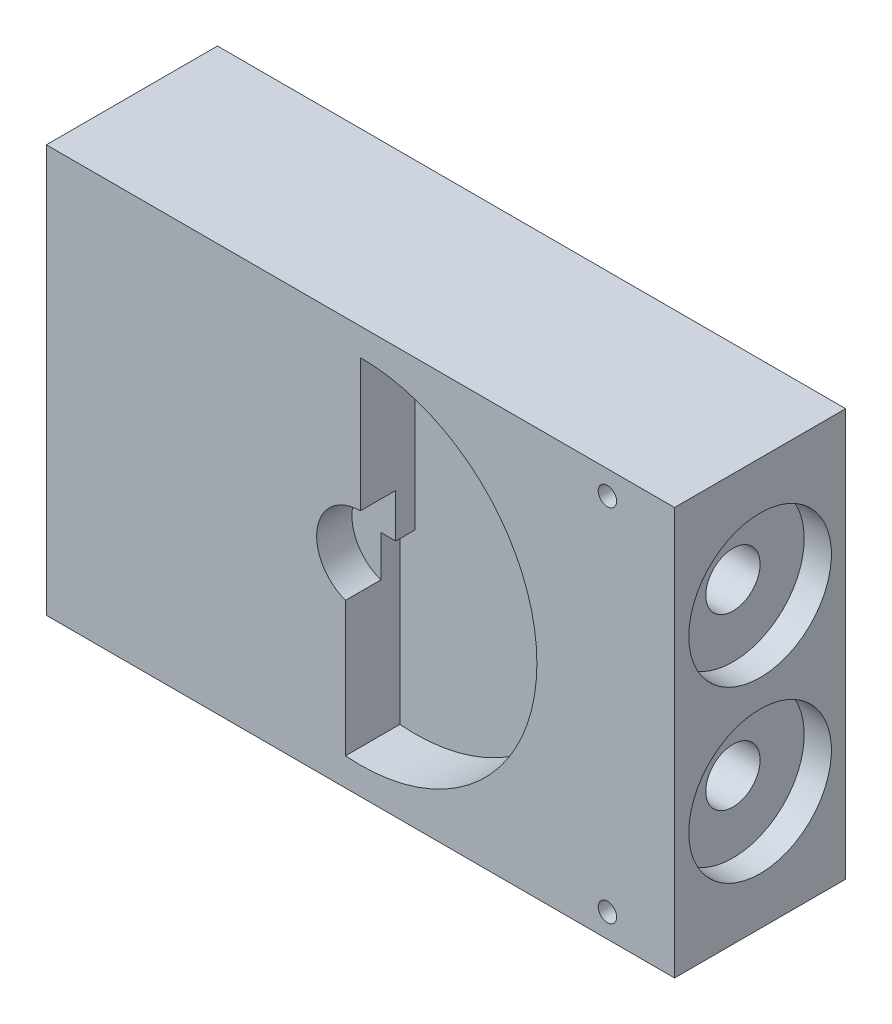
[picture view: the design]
ISO-10303-21;
HEADER;
FILE_DESCRIPTION(('STEP AP214'),'2;1');
FILE_NAME('part.step','',(''),(''),'','','');
FILE_SCHEMA(('AUTOMOTIVE_DESIGN { 1 0 10303 214 1 1 1 1 }'));
ENDSEC;
DATA;
#1=APPLICATION_CONTEXT('core data for automotive mechanical design processes');
#2=APPLICATION_PROTOCOL_DEFINITION('international standard','automotive_design',2000,#1);
#3=PRODUCT_CONTEXT('',#1,'mechanical');
#4=PRODUCT('Part','Part','',(#3));
#5=PRODUCT_RELATED_PRODUCT_CATEGORY('part','',(#4));
#6=PRODUCT_DEFINITION_FORMATION('','',#4);
#7=PRODUCT_DEFINITION_CONTEXT('part definition',#1,'design');
#8=PRODUCT_DEFINITION('design','',#6,#7);
#9=PRODUCT_DEFINITION_SHAPE('','',#8);
#10=(LENGTH_UNIT() NAMED_UNIT(*) SI_UNIT(.MILLI.,.METRE.));
#11=(NAMED_UNIT(*) PLANE_ANGLE_UNIT() SI_UNIT($,.RADIAN.));
#12=(NAMED_UNIT(*) SI_UNIT($,.STERADIAN.) SOLID_ANGLE_UNIT());
#13=UNCERTAINTY_MEASURE_WITH_UNIT(LENGTH_MEASURE(1.E-05),#10,'distance_accuracy_value','');
#14=(GEOMETRIC_REPRESENTATION_CONTEXT(3) GLOBAL_UNCERTAINTY_ASSIGNED_CONTEXT((#13)) GLOBAL_UNIT_ASSIGNED_CONTEXT((#10,
#11,#12)) REPRESENTATION_CONTEXT('',''));
#15=CARTESIAN_POINT('',(0.,0.,0.));
#16=DIRECTION('',(0.,0.,1.));
#17=DIRECTION('',(1.,0.,0.));
#18=AXIS2_PLACEMENT_3D('',#15,#16,#17);
#19=CARTESIAN_POINT('',(29.5275,-16.3368181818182,0.));
#20=DIRECTION('',(1.,0.,0.));
#21=DIRECTION('',(0.,0.,-1.));
#22=AXIS2_PLACEMENT_3D('',#19,#20,#21);
#23=PLANE('',#22);
#24=CARTESIAN_POINT('',(29.5275,-15.875,0.));
#25=DIRECTION('',(-1.,0.,0.));
#26=DIRECTION('',(0.,0.,1.));
#27=AXIS2_PLACEMENT_3D('',#24,#25,#26);
#28=CIRCLE('',#27,5.08);
#29=CARTESIAN_POINT('',(29.5275,-15.875,5.08));
#30=VERTEX_POINT('',#29);
#31=EDGE_CURVE('E224',#30,#30,#28,.F.);
#32=ORIENTED_EDGE('',*,*,#31,.T.);
#33=EDGE_LOOP('',(#32));
#34=FACE_BOUND('',#33,.T.);
#35=ADVANCED_FACE('F38',(#34),#23,.T.);
#36=CARTESIAN_POINT('',(29.5275,15.4131818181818,0.));
#37=DIRECTION('',(1.,0.,0.));
#38=DIRECTION('',(0.,0.,-1.));
#39=AXIS2_PLACEMENT_3D('',#36,#37,#38);
#40=PLANE('',#39);
#41=CARTESIAN_POINT('',(29.5275,15.875,0.));
#42=DIRECTION('',(-1.,0.,0.));
#43=DIRECTION('',(0.,0.,1.));
#44=AXIS2_PLACEMENT_3D('',#41,#42,#43);
#45=CIRCLE('',#44,5.08);
#46=CARTESIAN_POINT('',(29.5275,15.875,5.08000000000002));
#47=VERTEX_POINT('',#46);
#48=EDGE_CURVE('E221',#47,#47,#45,.F.);
#49=ORIENTED_EDGE('',*,*,#48,.T.);
#50=EDGE_LOOP('',(#49));
#51=FACE_BOUND('',#50,.T.);
#52=ADVANCED_FACE('F604',(#51),#40,.T.);
#53=CARTESIAN_POINT('',(53.6575,-15.875,0.));
#54=DIRECTION('',(-1.,0.,0.));
#55=DIRECTION('',(0.,0.,1.));
#56=AXIS2_PLACEMENT_3D('',#53,#54,#55);
#57=CYLINDRICAL_SURFACE('',#56,5.08);
#58=CARTESIAN_POINT('',(53.6575,-15.875,0.));
#59=DIRECTION('',(-1.,0.,0.));
#60=DIRECTION('',(0.,0.,1.));
#61=AXIS2_PLACEMENT_3D('',#58,#59,#60);
#62=CIRCLE('',#61,5.08);
#63=CARTESIAN_POINT('',(53.6575,-15.875,5.08));
#64=VERTEX_POINT('',#63);
#65=EDGE_CURVE('E218',#64,#64,#62,.T.);
#66=ORIENTED_EDGE('',*,*,#65,.F.);
#67=EDGE_LOOP('',(#66));
#68=FACE_BOUND('',#67,.T.);
#69=ORIENTED_EDGE('',*,*,#31,.F.);
#70=EDGE_LOOP('',(#69));
#71=FACE_BOUND('',#70,.T.);
#72=ADVANCED_FACE('F613',(#68,#71),#57,.F.);
#73=CARTESIAN_POINT('',(53.6575,15.875,0.));
#74=DIRECTION('',(-1.,0.,0.));
#75=DIRECTION('',(0.,0.,1.));
#76=AXIS2_PLACEMENT_3D('',#73,#74,#75);
#77=CYLINDRICAL_SURFACE('',#76,5.08);
#78=CARTESIAN_POINT('',(53.6575,15.875,0.));
#79=DIRECTION('',(-1.,0.,0.));
#80=DIRECTION('',(0.,0.,1.));
#81=AXIS2_PLACEMENT_3D('',#78,#79,#80);
#82=CIRCLE('',#81,5.08);
#83=CARTESIAN_POINT('',(53.6575,15.875,5.08000000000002));
#84=VERTEX_POINT('',#83);
#85=EDGE_CURVE('E215',#84,#84,#82,.T.);
#86=ORIENTED_EDGE('',*,*,#85,.F.);
#87=EDGE_LOOP('',(#86));
#88=FACE_BOUND('',#87,.T.);
#89=ORIENTED_EDGE('',*,*,#48,.F.);
#90=EDGE_LOOP('',(#89));
#91=FACE_BOUND('',#90,.T.);
#92=ADVANCED_FACE('F622',(#88,#91),#77,.F.);
#93=CARTESIAN_POINT('',(-32.0397909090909,0.,-6.35));
#94=DIRECTION('',(0.,0.,1.));
#95=DIRECTION('',(1.,0.,0.));
#96=AXIS2_PLACEMENT_3D('',#93,#94,#95);
#97=PLANE('',#96);
#98=CARTESIAN_POINT('',(-31.75,0.,-6.35));
#99=DIRECTION('',(0.,0.,1.));
#100=DIRECTION('',(1.,0.,0.));
#101=AXIS2_PLACEMENT_3D('',#98,#99,#100);
#102=CIRCLE('',#101,3.1877);
#103=CARTESIAN_POINT('',(-28.5623,0.,-6.35));
#104=VERTEX_POINT('',#103);
#105=EDGE_CURVE('E212',#104,#104,#102,.F.);
#106=ORIENTED_EDGE('',*,*,#105,.T.);
#107=EDGE_LOOP('',(#106));
#108=FACE_BOUND('',#107,.T.);
#109=ADVANCED_FACE('F631',(#108),#97,.F.);
#110=CARTESIAN_POINT('',(32.0386363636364,-31.75,-5.08));
#111=DIRECTION('',(0.,0.,1.));
#112=DIRECTION('',(1.,0.,0.));
#113=AXIS2_PLACEMENT_3D('',#110,#111,#112);
#114=PLANE('',#113);
#115=CARTESIAN_POINT('',(31.75,-31.75,-5.08));
#116=DIRECTION('',(0.,0.,1.));
#117=DIRECTION('',(1.,0.,0.));
#118=AXIS2_PLACEMENT_3D('',#115,#116,#117);
#119=CIRCLE('',#118,3.175);
#120=CARTESIAN_POINT('',(34.925,-31.75,-5.08));
#121=VERTEX_POINT('',#120);
#122=EDGE_CURVE('E209',#121,#121,#119,.F.);
#123=ORIENTED_EDGE('',*,*,#122,.T.);
#124=EDGE_LOOP('',(#123));
#125=FACE_BOUND('',#124,.T.);
#126=ADVANCED_FACE('F400',(#125),#114,.F.);
#127=CARTESIAN_POINT('',(28.575,28.5115,-5.08));
#128=DIRECTION('',(0.,0.,1.));
#129=DIRECTION('',(1.,0.,0.));
#130=AXIS2_PLACEMENT_3D('',#127,#128,#129);
#131=PLANE('',#130);
#132=CARTESIAN_POINT('',(31.75,31.75,-5.08));
#133=DIRECTION('',(0.,0.,1.));
#134=DIRECTION('',(1.,0.,0.));
#135=AXIS2_PLACEMENT_3D('',#132,#133,#134);
#136=CIRCLE('',#135,3.175);
#137=CARTESIAN_POINT('',(34.925,31.75,-5.08));
#138=VERTEX_POINT('',#137);
#139=EDGE_CURVE('E206',#138,#138,#136,.F.);
#140=ORIENTED_EDGE('',*,*,#139,.T.);
#141=EDGE_LOOP('',(#140));
#142=FACE_BOUND('',#141,.T.);
#143=ADVANCED_FACE('F396',(#142),#131,.F.);
#144=CARTESIAN_POINT('',(32.0397909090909,0.,-6.35));
#145=DIRECTION('',(0.,0.,1.));
#146=DIRECTION('',(1.,0.,0.));
#147=AXIS2_PLACEMENT_3D('',#144,#145,#146);
#148=PLANE('',#147);
#149=CARTESIAN_POINT('',(31.75,0.,-6.35));
#150=DIRECTION('',(0.,0.,1.));
#151=DIRECTION('',(1.,0.,0.));
#152=AXIS2_PLACEMENT_3D('',#149,#150,#151);
#153=CIRCLE('',#152,3.1877);
#154=CARTESIAN_POINT('',(34.9377,0.,-6.35));
#155=VERTEX_POINT('',#154);
#156=EDGE_CURVE('E203',#155,#155,#153,.F.);
#157=ORIENTED_EDGE('',*,*,#156,.T.);
#158=EDGE_LOOP('',(#157));
#159=FACE_BOUND('',#158,.T.);
#160=ADVANCED_FACE('F399',(#159),#148,.F.);
#161=CARTESIAN_POINT('',(-28.575,-28.5115,-5.08));
#162=DIRECTION('',(0.,0.,1.));
#163=DIRECTION('',(-1.,0.,0.));
#164=AXIS2_PLACEMENT_3D('',#161,#162,#163);
#165=PLANE('',#164);
#166=CARTESIAN_POINT('',(-31.75,-31.75,-5.08));
#167=DIRECTION('',(0.,0.,1.));
#168=DIRECTION('',(1.,0.,0.));
#169=AXIS2_PLACEMENT_3D('',#166,#167,#168);
#170=CIRCLE('',#169,3.175);
#171=CARTESIAN_POINT('',(-28.575,-31.75,-5.08));
#172=VERTEX_POINT('',#171);
#173=EDGE_CURVE('E200',#172,#172,#170,.F.);
#174=ORIENTED_EDGE('',*,*,#173,.T.);
#175=EDGE_LOOP('',(#174));
#176=FACE_BOUND('',#175,.T.);
#177=ADVANCED_FACE('F402',(#176),#165,.F.);
#178=CARTESIAN_POINT('',(-32.0386363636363,31.75,-5.08));
#179=DIRECTION('',(0.,0.,1.));
#180=DIRECTION('',(1.,0.,0.));
#181=AXIS2_PLACEMENT_3D('',#178,#179,#180);
#182=PLANE('',#181);
#183=CARTESIAN_POINT('',(-31.75,31.75,-5.08));
#184=DIRECTION('',(0.,0.,1.));
#185=DIRECTION('',(1.,0.,0.));
#186=AXIS2_PLACEMENT_3D('',#183,#184,#185);
#187=CIRCLE('',#186,3.175);
#188=CARTESIAN_POINT('',(-28.575,31.75,-5.08));
#189=VERTEX_POINT('',#188);
#190=EDGE_CURVE('E197',#189,#189,#187,.F.);
#191=ORIENTED_EDGE('',*,*,#190,.T.);
#192=EDGE_LOOP('',(#191));
#193=FACE_BOUND('',#192,.T.);
#194=ADVANCED_FACE('F405',(#193),#182,.F.);
#195=CARTESIAN_POINT('',(53.6575,-17.0872727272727,0.));
#196=DIRECTION('',(1.,0.,0.));
#197=DIRECTION('',(0.,0.,-1.));
#198=AXIS2_PLACEMENT_3D('',#195,#196,#197);
#199=PLANE('',#198);
#200=ORIENTED_EDGE('',*,*,#65,.T.);
#201=EDGE_LOOP('',(#200));
#202=FACE_BOUND('',#201,.T.);
#203=CARTESIAN_POINT('',(53.6575,-15.875,0.));
#204=DIRECTION('',(-1.,0.,0.));
#205=DIRECTION('',(0.,0.,1.));
#206=AXIS2_PLACEMENT_3D('',#203,#204,#205);
#207=CIRCLE('',#206,13.335);
#208=CARTESIAN_POINT('',(53.6575,-15.875,13.335));
#209=VERTEX_POINT('',#208);
#210=EDGE_CURVE('E194',#209,#209,#207,.F.);
#211=ORIENTED_EDGE('',*,*,#210,.T.);
#212=EDGE_LOOP('',(#211));
#213=FACE_BOUND('',#212,.T.);
#214=ADVANCED_FACE('F664',(#202,#213),#199,.T.);
#215=CARTESIAN_POINT('',(53.6575,14.6627272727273,0.));
#216=DIRECTION('',(1.,0.,0.));
#217=DIRECTION('',(0.,0.,-1.));
#218=AXIS2_PLACEMENT_3D('',#215,#216,#217);
#219=PLANE('',#218);
#220=ORIENTED_EDGE('',*,*,#85,.T.);
#221=EDGE_LOOP('',(#220));
#222=FACE_BOUND('',#221,.T.);
#223=CARTESIAN_POINT('',(53.6575,15.875,0.));
#224=DIRECTION('',(-1.,0.,0.));
#225=DIRECTION('',(0.,0.,1.));
#226=AXIS2_PLACEMENT_3D('',#223,#224,#225);
#227=CIRCLE('',#226,13.335);
#228=CARTESIAN_POINT('',(53.6575,15.875,13.335));
#229=VERTEX_POINT('',#228);
#230=EDGE_CURVE('E191',#229,#229,#227,.F.);
#231=ORIENTED_EDGE('',*,*,#230,.T.);
#232=EDGE_LOOP('',(#231));
#233=FACE_BOUND('',#232,.T.);
#234=ADVANCED_FACE('F673',(#222,#233),#219,.T.);
#235=CARTESIAN_POINT('',(-56.7375,-18.5963723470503,0.));
#236=DIRECTION('',(1.,0.,0.));
#237=DIRECTION('',(0.,0.,-1.));
#238=AXIS2_PLACEMENT_3D('',#235,#236,#237);
#239=PLANE('',#238);
#240=CARTESIAN_POINT('',(-56.7375,-19.05,0.));
#241=DIRECTION('',(1.,0.,0.));
#242=DIRECTION('',(0.,0.,-1.));
#243=AXIS2_PLACEMENT_3D('',#240,#241,#242);
#244=CIRCLE('',#243,4.9899041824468);
#245=CARTESIAN_POINT('',(-56.7375,-19.05,-4.9899041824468));
#246=VERTEX_POINT('',#245);
#247=EDGE_CURVE('E188',#246,#246,#244,.F.);
#248=ORIENTED_EDGE('',*,*,#247,.T.);
#249=EDGE_LOOP('',(#248));
#250=FACE_BOUND('',#249,.T.);
#251=ADVANCED_FACE('F682',(#250),#239,.F.);
#252=CARTESIAN_POINT('',(-55.6895,6.75409090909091,0.));
#253=DIRECTION('',(1.,0.,0.));
#254=DIRECTION('',(0.,0.,-1.));
#255=AXIS2_PLACEMENT_3D('',#252,#253,#254);
#256=PLANE('',#255);
#257=CARTESIAN_POINT('',(-55.6895,7.11200000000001,0.));
#258=DIRECTION('',(-1.,0.,0.));
#259=DIRECTION('',(0.,0.,1.));
#260=AXIS2_PLACEMENT_3D('',#257,#258,#259);
#261=CIRCLE('',#260,3.937);
#262=CARTESIAN_POINT('',(-55.6895,7.11200000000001,3.937));
#263=VERTEX_POINT('',#262);
#264=EDGE_CURVE('E185',#263,#263,#261,.T.);
#265=ORIENTED_EDGE('',*,*,#264,.T.);
#266=EDGE_LOOP('',(#265));
#267=FACE_BOUND('',#266,.T.);
#268=ADVANCED_FACE('F691',(#267),#256,.F.);
#269=CARTESIAN_POINT('',(-55.6895,-7.46990909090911,0.));
#270=DIRECTION('',(1.,0.,0.));
#271=DIRECTION('',(0.,0.,-1.));
#272=AXIS2_PLACEMENT_3D('',#269,#270,#271);
#273=PLANE('',#272);
#274=CARTESIAN_POINT('',(-55.6895,-7.11200000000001,0.));
#275=DIRECTION('',(-1.,0.,0.));
#276=DIRECTION('',(0.,0.,1.));
#277=AXIS2_PLACEMENT_3D('',#274,#275,#276);
#278=CIRCLE('',#277,3.937);
#279=CARTESIAN_POINT('',(-55.6895,-7.11200000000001,3.937));
#280=VERTEX_POINT('',#279);
#281=EDGE_CURVE('E182',#280,#280,#278,.T.);
#282=ORIENTED_EDGE('',*,*,#281,.T.);
#283=EDGE_LOOP('',(#282));
#284=FACE_BOUND('',#283,.T.);
#285=ADVANCED_FACE('F700',(#284),#273,.F.);
#286=CARTESIAN_POINT('',(-56.1975,-32.1367727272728,7.11200000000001));
#287=DIRECTION('',(1.,0.,0.));
#288=DIRECTION('',(0.,0.,-1.));
#289=AXIS2_PLACEMENT_3D('',#286,#287,#288);
#290=PLANE('',#289);
#291=CARTESIAN_POINT('',(-56.1975,-31.75,7.11200000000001));
#292=DIRECTION('',(-1.,0.,0.));
#293=DIRECTION('',(0.,0.,1.));
#294=AXIS2_PLACEMENT_3D('',#291,#292,#293);
#295=CIRCLE('',#294,4.2545);
#296=CARTESIAN_POINT('',(-56.1975,-31.75,11.3665));
#297=VERTEX_POINT('',#296);
#298=EDGE_CURVE('E179',#297,#297,#295,.T.);
#299=ORIENTED_EDGE('',*,*,#298,.T.);
#300=EDGE_LOOP('',(#299));
#301=FACE_BOUND('',#300,.T.);
#302=ADVANCED_FACE('F411',(#301),#290,.F.);
#303=CARTESIAN_POINT('',(-56.1975,4.2545,-11.45159));
#304=DIRECTION('',(1.,0.,0.));
#305=DIRECTION('',(0.,0.,1.));
#306=AXIS2_PLACEMENT_3D('',#303,#304,#305);
#307=PLANE('',#306);
#308=CARTESIAN_POINT('',(-56.1975,0.,-7.112));
#309=DIRECTION('',(-1.,0.,0.));
#310=DIRECTION('',(0.,0.,1.));
#311=AXIS2_PLACEMENT_3D('',#308,#309,#310);
#312=CIRCLE('',#311,4.2545);
#313=CARTESIAN_POINT('',(-56.1975,0.,-2.8575));
#314=VERTEX_POINT('',#313);
#315=EDGE_CURVE('E176',#314,#314,#312,.T.);
#316=ORIENTED_EDGE('',*,*,#315,.T.);
#317=EDGE_LOOP('',(#316));
#318=FACE_BOUND('',#317,.T.);
#319=ADVANCED_FACE('F407',(#318),#307,.F.);
#320=CARTESIAN_POINT('',(-56.1975,27.4955,11.45159));
#321=DIRECTION('',(1.,0.,0.));
#322=DIRECTION('',(0.,0.,-1.));
#323=AXIS2_PLACEMENT_3D('',#320,#321,#322);
#324=PLANE('',#323);
#325=CARTESIAN_POINT('',(-56.1975,31.75,7.11200000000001));
#326=DIRECTION('',(-1.,0.,0.));
#327=DIRECTION('',(0.,0.,1.));
#328=AXIS2_PLACEMENT_3D('',#325,#326,#327);
#329=CIRCLE('',#328,4.2545);
#330=CARTESIAN_POINT('',(-56.1975,31.75,11.3665));
#331=VERTEX_POINT('',#330);
#332=EDGE_CURVE('E173',#331,#331,#329,.T.);
#333=ORIENTED_EDGE('',*,*,#332,.T.);
#334=EDGE_LOOP('',(#333));
#335=FACE_BOUND('',#334,.T.);
#336=ADVANCED_FACE('F410',(#335),#324,.F.);
#337=CARTESIAN_POINT('',(-56.1975,32.1367727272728,-7.112));
#338=DIRECTION('',(1.,0.,0.));
#339=DIRECTION('',(0.,0.,-1.));
#340=AXIS2_PLACEMENT_3D('',#337,#338,#339);
#341=PLANE('',#340);
#342=CARTESIAN_POINT('',(-56.1975,31.75,-7.112));
#343=DIRECTION('',(-1.,0.,0.));
#344=DIRECTION('',(0.,0.,1.));
#345=AXIS2_PLACEMENT_3D('',#342,#343,#344);
#346=CIRCLE('',#345,4.2545);
#347=CARTESIAN_POINT('',(-56.1975,31.75,-2.8575));
#348=VERTEX_POINT('',#347);
#349=EDGE_CURVE('E170',#348,#348,#346,.T.);
#350=ORIENTED_EDGE('',*,*,#349,.T.);
#351=EDGE_LOOP('',(#350));
#352=FACE_BOUND('',#351,.T.);
#353=ADVANCED_FACE('F415',(#352),#341,.F.);
#354=CARTESIAN_POINT('',(-56.1975,-0.386772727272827,7.112));
#355=DIRECTION('',(1.,0.,0.));
#356=DIRECTION('',(0.,0.,-1.));
#357=AXIS2_PLACEMENT_3D('',#354,#355,#356);
#358=PLANE('',#357);
#359=CARTESIAN_POINT('',(-56.1975,0.,7.112));
#360=DIRECTION('',(-1.,0.,0.));
#361=DIRECTION('',(0.,0.,1.));
#362=AXIS2_PLACEMENT_3D('',#359,#360,#361);
#363=CIRCLE('',#362,4.2545);
#364=CARTESIAN_POINT('',(-56.1975,0.,11.3665));
#365=VERTEX_POINT('',#364);
#366=EDGE_CURVE('E167',#365,#365,#363,.T.);
#367=ORIENTED_EDGE('',*,*,#366,.T.);
#368=EDGE_LOOP('',(#367));
#369=FACE_BOUND('',#368,.T.);
#370=ADVANCED_FACE('F421',(#369),#358,.F.);
#371=CARTESIAN_POINT('',(-56.1975,-27.4955,-11.45159));
#372=DIRECTION('',(1.,0.,0.));
#373=DIRECTION('',(0.,0.,1.));
#374=AXIS2_PLACEMENT_3D('',#371,#372,#373);
#375=PLANE('',#374);
#376=CARTESIAN_POINT('',(-56.1975,-31.75,-7.11200000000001));
#377=DIRECTION('',(-1.,0.,0.));
#378=DIRECTION('',(0.,0.,1.));
#379=AXIS2_PLACEMENT_3D('',#376,#377,#378);
#380=CIRCLE('',#379,4.2545);
#381=CARTESIAN_POINT('',(-56.1975,-31.75,-2.8575));
#382=VERTEX_POINT('',#381);
#383=EDGE_CURVE('E164',#382,#382,#380,.T.);
#384=ORIENTED_EDGE('',*,*,#383,.T.);
#385=EDGE_LOOP('',(#384));
#386=FACE_BOUND('',#385,.T.);
#387=ADVANCED_FACE('F417',(#386),#375,.F.);
#388=CARTESIAN_POINT('',(-31.75,0.,-16.002));
#389=DIRECTION('',(0.,0.,1.));
#390=DIRECTION('',(1.,0.,0.));
#391=AXIS2_PLACEMENT_3D('',#388,#389,#390);
#392=CYLINDRICAL_SURFACE('',#391,3.1877);
#393=ORIENTED_EDGE('',*,*,#105,.F.);
#394=EDGE_LOOP('',(#393));
#395=FACE_BOUND('',#394,.T.);
#396=CARTESIAN_POINT('',(-31.75,0.,-16.002));
#397=DIRECTION('',(0.,0.,1.));
#398=DIRECTION('',(1.,0.,0.));
#399=AXIS2_PLACEMENT_3D('',#396,#397,#398);
#400=CIRCLE('',#399,3.1877);
#401=CARTESIAN_POINT('',(-28.5623,0.,-16.002));
#402=VERTEX_POINT('',#401);
#403=EDGE_CURVE('E161',#402,#402,#400,.F.);
#404=ORIENTED_EDGE('',*,*,#403,.T.);
#405=EDGE_LOOP('',(#404));
#406=FACE_BOUND('',#405,.T.);
#407=ADVANCED_FACE('F420',(#395,#406),#392,.F.);
#408=CARTESIAN_POINT('',(31.75,-31.75,-16.002));
#409=DIRECTION('',(0.,0.,1.));
#410=DIRECTION('',(1.,0.,0.));
#411=AXIS2_PLACEMENT_3D('',#408,#409,#410);
#412=CYLINDRICAL_SURFACE('',#411,3.175);
#413=ORIENTED_EDGE('',*,*,#122,.F.);
#414=EDGE_LOOP('',(#413));
#415=FACE_BOUND('',#414,.T.);
#416=CARTESIAN_POINT('',(31.75,-31.75,-16.002));
#417=DIRECTION('',(0.,0.,1.));
#418=DIRECTION('',(1.,0.,0.));
#419=AXIS2_PLACEMENT_3D('',#416,#417,#418);
#420=CIRCLE('',#419,3.175);
#421=CARTESIAN_POINT('',(34.925,-31.75,-16.002));
#422=VERTEX_POINT('',#421);
#423=EDGE_CURVE('E158',#422,#422,#420,.F.);
#424=ORIENTED_EDGE('',*,*,#423,.T.);
#425=EDGE_LOOP('',(#424));
#426=FACE_BOUND('',#425,.T.);
#427=ADVANCED_FACE('F427',(#415,#426),#412,.F.);
#428=CARTESIAN_POINT('',(31.75,31.75,-16.002));
#429=DIRECTION('',(0.,0.,1.));
#430=DIRECTION('',(1.,0.,0.));
#431=AXIS2_PLACEMENT_3D('',#428,#429,#430);
#432=CYLINDRICAL_SURFACE('',#431,3.175);
#433=ORIENTED_EDGE('',*,*,#139,.F.);
#434=EDGE_LOOP('',(#433));
#435=FACE_BOUND('',#434,.T.);
#436=CARTESIAN_POINT('',(31.75,31.75,-16.002));
#437=DIRECTION('',(0.,0.,1.));
#438=DIRECTION('',(1.,0.,0.));
#439=AXIS2_PLACEMENT_3D('',#436,#437,#438);
#440=CIRCLE('',#439,3.175);
#441=CARTESIAN_POINT('',(34.925,31.75,-16.002));
#442=VERTEX_POINT('',#441);
#443=EDGE_CURVE('E155',#442,#442,#440,.F.);
#444=ORIENTED_EDGE('',*,*,#443,.T.);
#445=EDGE_LOOP('',(#444));
#446=FACE_BOUND('',#445,.T.);
#447=ADVANCED_FACE('F423',(#435,#446),#432,.F.);
#448=CARTESIAN_POINT('',(31.75,0.,-16.002));
#449=DIRECTION('',(0.,0.,1.));
#450=DIRECTION('',(1.,0.,0.));
#451=AXIS2_PLACEMENT_3D('',#448,#449,#450);
#452=CYLINDRICAL_SURFACE('',#451,3.1877);
#453=ORIENTED_EDGE('',*,*,#156,.F.);
#454=EDGE_LOOP('',(#453));
#455=FACE_BOUND('',#454,.T.);
#456=CARTESIAN_POINT('',(31.75,0.,-16.002));
#457=DIRECTION('',(0.,0.,1.));
#458=DIRECTION('',(1.,0.,0.));
#459=AXIS2_PLACEMENT_3D('',#456,#457,#458);
#460=CIRCLE('',#459,3.1877);
#461=CARTESIAN_POINT('',(34.9377,0.,-16.002));
#462=VERTEX_POINT('',#461);
#463=EDGE_CURVE('E152',#462,#462,#460,.F.);
#464=ORIENTED_EDGE('',*,*,#463,.T.);
#465=EDGE_LOOP('',(#464));
#466=FACE_BOUND('',#465,.T.);
#467=ADVANCED_FACE('F426',(#455,#466),#452,.F.);
#468=CARTESIAN_POINT('',(-31.75,-31.75,-16.002));
#469=DIRECTION('',(0.,0.,1.));
#470=DIRECTION('',(1.,0.,0.));
#471=AXIS2_PLACEMENT_3D('',#468,#469,#470);
#472=CYLINDRICAL_SURFACE('',#471,3.175);
#473=ORIENTED_EDGE('',*,*,#173,.F.);
#474=EDGE_LOOP('',(#473));
#475=FACE_BOUND('',#474,.T.);
#476=CARTESIAN_POINT('',(-31.75,-31.75,-16.002));
#477=DIRECTION('',(0.,0.,1.));
#478=DIRECTION('',(1.,0.,0.));
#479=AXIS2_PLACEMENT_3D('',#476,#477,#478);
#480=CIRCLE('',#479,3.175);
#481=CARTESIAN_POINT('',(-28.575,-31.75,-16.002));
#482=VERTEX_POINT('',#481);
#483=EDGE_CURVE('E149',#482,#482,#480,.F.);
#484=ORIENTED_EDGE('',*,*,#483,.T.);
#485=EDGE_LOOP('',(#484));
#486=FACE_BOUND('',#485,.T.);
#487=ADVANCED_FACE('F429',(#475,#486),#472,.F.);
#488=CARTESIAN_POINT('',(-31.75,31.75,-16.002));
#489=DIRECTION('',(0.,0.,1.));
#490=DIRECTION('',(1.,0.,0.));
#491=AXIS2_PLACEMENT_3D('',#488,#489,#490);
#492=CYLINDRICAL_SURFACE('',#491,3.175);
#493=ORIENTED_EDGE('',*,*,#190,.F.);
#494=EDGE_LOOP('',(#493));
#495=FACE_BOUND('',#494,.T.);
#496=CARTESIAN_POINT('',(-31.75,31.75,-16.002));
#497=DIRECTION('',(0.,0.,1.));
#498=DIRECTION('',(1.,0.,0.));
#499=AXIS2_PLACEMENT_3D('',#496,#497,#498);
#500=CIRCLE('',#499,3.175);
#501=CARTESIAN_POINT('',(-28.575,31.75,-16.002));
#502=VERTEX_POINT('',#501);
#503=EDGE_CURVE('E146',#502,#502,#500,.F.);
#504=ORIENTED_EDGE('',*,*,#503,.T.);
#505=EDGE_LOOP('',(#504));
#506=FACE_BOUND('',#505,.T.);
#507=ADVANCED_FACE('F432',(#495,#506),#492,.F.);
#508=CARTESIAN_POINT('',(58.7375,-15.875,0.));
#509=DIRECTION('',(-1.,0.,0.));
#510=DIRECTION('',(0.,0.,1.));
#511=AXIS2_PLACEMENT_3D('',#508,#509,#510);
#512=CYLINDRICAL_SURFACE('',#511,13.335);
#513=ORIENTED_EDGE('',*,*,#210,.F.);
#514=EDGE_LOOP('',(#513));
#515=FACE_BOUND('',#514,.T.);
#516=CARTESIAN_POINT('',(58.7375,-15.875,0.));
#517=DIRECTION('',(-1.,0.,0.));
#518=DIRECTION('',(0.,0.,1.));
#519=AXIS2_PLACEMENT_3D('',#516,#517,#518);
#520=CIRCLE('',#519,13.335);
#521=CARTESIAN_POINT('',(58.7375,-15.875,13.335));
#522=VERTEX_POINT('',#521);
#523=EDGE_CURVE('E143',#522,#522,#520,.F.);
#524=ORIENTED_EDGE('',*,*,#523,.T.);
#525=EDGE_LOOP('',(#524));
#526=FACE_BOUND('',#525,.T.);
#527=ADVANCED_FACE('F480',(#515,#526),#512,.F.);
#528=CARTESIAN_POINT('',(58.7375,15.875,0.));
#529=DIRECTION('',(-1.,0.,0.));
#530=DIRECTION('',(0.,0.,1.));
#531=AXIS2_PLACEMENT_3D('',#528,#529,#530);
#532=CYLINDRICAL_SURFACE('',#531,13.335);
#533=ORIENTED_EDGE('',*,*,#230,.F.);
#534=EDGE_LOOP('',(#533));
#535=FACE_BOUND('',#534,.T.);
#536=CARTESIAN_POINT('',(58.7375,15.875,0.));
#537=DIRECTION('',(-1.,0.,0.));
#538=DIRECTION('',(0.,0.,1.));
#539=AXIS2_PLACEMENT_3D('',#536,#537,#538);
#540=CIRCLE('',#539,13.335);
#541=CARTESIAN_POINT('',(58.7375,15.875,13.335));
#542=VERTEX_POINT('',#541);
#543=EDGE_CURVE('E140',#542,#542,#540,.F.);
#544=ORIENTED_EDGE('',*,*,#543,.T.);
#545=EDGE_LOOP('',(#544));
#546=FACE_BOUND('',#545,.T.);
#547=ADVANCED_FACE('F470',(#535,#546),#532,.F.);
#548=CARTESIAN_POINT('',(-58.7375,-19.05,0.));
#549=DIRECTION('',(1.,0.,0.));
#550=DIRECTION('',(0.,0.,-1.));
#551=AXIS2_PLACEMENT_3D('',#548,#549,#550);
#552=CYLINDRICAL_SURFACE('',#551,4.9899041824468);
#553=ORIENTED_EDGE('',*,*,#247,.F.);
#554=EDGE_LOOP('',(#553));
#555=FACE_BOUND('',#554,.T.);
#556=CARTESIAN_POINT('',(-58.7375,-19.05,0.));
#557=DIRECTION('',(1.,0.,0.));
#558=DIRECTION('',(0.,0.,-1.));
#559=AXIS2_PLACEMENT_3D('',#556,#557,#558);
#560=CIRCLE('',#559,4.9899041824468);
#561=CARTESIAN_POINT('',(-58.7375,-19.05,-4.9899041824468));
#562=VERTEX_POINT('',#561);
#563=EDGE_CURVE('E137',#562,#562,#560,.F.);
#564=ORIENTED_EDGE('',*,*,#563,.T.);
#565=EDGE_LOOP('',(#564));
#566=FACE_BOUND('',#565,.T.);
#567=ADVANCED_FACE('F467',(#555,#566),#552,.F.);
#568=CARTESIAN_POINT('',(-55.6895,7.11200000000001,0.));
#569=DIRECTION('',(-1.,0.,0.));
#570=DIRECTION('',(0.,0.,1.));
#571=AXIS2_PLACEMENT_3D('',#568,#569,#570);
#572=CYLINDRICAL_SURFACE('',#571,3.937);
#573=CARTESIAN_POINT('',(-58.7375,7.11200000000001,0.));
#574=DIRECTION('',(-1.,0.,0.));
#575=DIRECTION('',(0.,0.,1.));
#576=AXIS2_PLACEMENT_3D('',#573,#574,#575);
#577=CIRCLE('',#576,3.937);
#578=CARTESIAN_POINT('',(-58.7375,7.11200000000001,3.937));
#579=VERTEX_POINT('',#578);
#580=EDGE_CURVE('E134',#579,#579,#577,.T.);
#581=ORIENTED_EDGE('',*,*,#580,.T.);
#582=EDGE_LOOP('',(#581));
#583=FACE_BOUND('',#582,.T.);
#584=ORIENTED_EDGE('',*,*,#264,.F.);
#585=EDGE_LOOP('',(#584));
#586=FACE_BOUND('',#585,.T.);
#587=ADVANCED_FACE('F469',(#583,#586),#572,.F.);
#588=CARTESIAN_POINT('',(-55.6895,-7.11200000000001,0.));
#589=DIRECTION('',(-1.,0.,0.));
#590=DIRECTION('',(0.,0.,1.));
#591=AXIS2_PLACEMENT_3D('',#588,#589,#590);
#592=CYLINDRICAL_SURFACE('',#591,3.937);
#593=CARTESIAN_POINT('',(-58.7375,-7.11200000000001,0.));
#594=DIRECTION('',(-1.,0.,0.));
#595=DIRECTION('',(0.,0.,1.));
#596=AXIS2_PLACEMENT_3D('',#593,#594,#595);
#597=CIRCLE('',#596,3.937);
#598=CARTESIAN_POINT('',(-58.7375,-7.11200000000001,3.937));
#599=VERTEX_POINT('',#598);
#600=EDGE_CURVE('E131',#599,#599,#597,.T.);
#601=ORIENTED_EDGE('',*,*,#600,.T.);
#602=EDGE_LOOP('',(#601));
#603=FACE_BOUND('',#602,.T.);
#604=ORIENTED_EDGE('',*,*,#281,.F.);
#605=EDGE_LOOP('',(#604));
#606=FACE_BOUND('',#605,.T.);
#607=ADVANCED_FACE('F477',(#603,#606),#592,.F.);
#608=CARTESIAN_POINT('',(-56.1975,-31.75,7.11200000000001));
#609=DIRECTION('',(-1.,0.,0.));
#610=DIRECTION('',(0.,0.,1.));
#611=AXIS2_PLACEMENT_3D('',#608,#609,#610);
#612=CYLINDRICAL_SURFACE('',#611,4.2545);
#613=ORIENTED_EDGE('',*,*,#298,.F.);
#614=EDGE_LOOP('',(#613));
#615=FACE_BOUND('',#614,.T.);
#616=CARTESIAN_POINT('',(-58.7375,-31.75,7.11200000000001));
#617=DIRECTION('',(-1.,0.,0.));
#618=DIRECTION('',(0.,0.,1.));
#619=AXIS2_PLACEMENT_3D('',#616,#617,#618);
#620=CIRCLE('',#619,4.2545);
#621=CARTESIAN_POINT('',(-58.7375,-31.75,11.3665));
#622=VERTEX_POINT('',#621);
#623=EDGE_CURVE('E128',#622,#622,#620,.T.);
#624=ORIENTED_EDGE('',*,*,#623,.T.);
#625=EDGE_LOOP('',(#624));
#626=FACE_BOUND('',#625,.T.);
#627=ADVANCED_FACE('F437',(#615,#626),#612,.F.);
#628=CARTESIAN_POINT('',(-56.1975,0.,-7.112));
#629=DIRECTION('',(-1.,0.,0.));
#630=DIRECTION('',(0.,0.,1.));
#631=AXIS2_PLACEMENT_3D('',#628,#629,#630);
#632=CYLINDRICAL_SURFACE('',#631,4.2545);
#633=ORIENTED_EDGE('',*,*,#315,.F.);
#634=EDGE_LOOP('',(#633));
#635=FACE_BOUND('',#634,.T.);
#636=CARTESIAN_POINT('',(-58.7375,0.,-7.112));
#637=DIRECTION('',(-1.,0.,0.));
#638=DIRECTION('',(0.,0.,1.));
#639=AXIS2_PLACEMENT_3D('',#636,#637,#638);
#640=CIRCLE('',#639,4.2545);
#641=CARTESIAN_POINT('',(-58.7375,0.,-2.8575));
#642=VERTEX_POINT('',#641);
#643=EDGE_CURVE('E125',#642,#642,#640,.T.);
#644=ORIENTED_EDGE('',*,*,#643,.T.);
#645=EDGE_LOOP('',(#644));
#646=FACE_BOUND('',#645,.T.);
#647=ADVANCED_FACE('F434',(#635,#646),#632,.F.);
#648=CARTESIAN_POINT('',(-56.1975,31.75,7.11200000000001));
#649=DIRECTION('',(-1.,0.,0.));
#650=DIRECTION('',(0.,0.,1.));
#651=AXIS2_PLACEMENT_3D('',#648,#649,#650);
#652=CYLINDRICAL_SURFACE('',#651,4.2545);
#653=ORIENTED_EDGE('',*,*,#332,.F.);
#654=EDGE_LOOP('',(#653));
#655=FACE_BOUND('',#654,.T.);
#656=CARTESIAN_POINT('',(-58.7375,31.75,7.11200000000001));
#657=DIRECTION('',(-1.,0.,0.));
#658=DIRECTION('',(0.,0.,1.));
#659=AXIS2_PLACEMENT_3D('',#656,#657,#658);
#660=CIRCLE('',#659,4.2545);
#661=CARTESIAN_POINT('',(-58.7375,31.75,11.3665));
#662=VERTEX_POINT('',#661);
#663=EDGE_CURVE('E122',#662,#662,#660,.T.);
#664=ORIENTED_EDGE('',*,*,#663,.T.);
#665=EDGE_LOOP('',(#664));
#666=FACE_BOUND('',#665,.T.);
#667=ADVANCED_FACE('F436',(#655,#666),#652,.F.);
#668=CARTESIAN_POINT('',(-56.1975,31.75,-7.112));
#669=DIRECTION('',(-1.,0.,0.));
#670=DIRECTION('',(0.,0.,1.));
#671=AXIS2_PLACEMENT_3D('',#668,#669,#670);
#672=CYLINDRICAL_SURFACE('',#671,4.2545);
#673=ORIENTED_EDGE('',*,*,#349,.F.);
#674=EDGE_LOOP('',(#673));
#675=FACE_BOUND('',#674,.T.);
#676=CARTESIAN_POINT('',(-58.7375,31.75,-7.112));
#677=DIRECTION('',(-1.,0.,0.));
#678=DIRECTION('',(0.,0.,1.));
#679=AXIS2_PLACEMENT_3D('',#676,#677,#678);
#680=CIRCLE('',#679,4.2545);
#681=CARTESIAN_POINT('',(-58.7375,31.75,-2.8575));
#682=VERTEX_POINT('',#681);
#683=EDGE_CURVE('E119',#682,#682,#680,.T.);
#684=ORIENTED_EDGE('',*,*,#683,.T.);
#685=EDGE_LOOP('',(#684));
#686=FACE_BOUND('',#685,.T.);
#687=ADVANCED_FACE('F440',(#675,#686),#672,.F.);
#688=CARTESIAN_POINT('',(-56.1975,0.,7.112));
#689=DIRECTION('',(-1.,0.,0.));
#690=DIRECTION('',(0.,0.,1.));
#691=AXIS2_PLACEMENT_3D('',#688,#689,#690);
#692=CYLINDRICAL_SURFACE('',#691,4.2545);
#693=ORIENTED_EDGE('',*,*,#366,.F.);
#694=EDGE_LOOP('',(#693));
#695=FACE_BOUND('',#694,.T.);
#696=CARTESIAN_POINT('',(-58.7375,0.,7.112));
#697=DIRECTION('',(-1.,0.,0.));
#698=DIRECTION('',(0.,0.,1.));
#699=AXIS2_PLACEMENT_3D('',#696,#697,#698);
#700=CIRCLE('',#699,4.2545);
#701=CARTESIAN_POINT('',(-58.7375,0.,11.3665));
#702=VERTEX_POINT('',#701);
#703=EDGE_CURVE('E116',#702,#702,#700,.T.);
#704=ORIENTED_EDGE('',*,*,#703,.T.);
#705=EDGE_LOOP('',(#704));
#706=FACE_BOUND('',#705,.T.);
#707=ADVANCED_FACE('F445',(#695,#706),#692,.F.);
#708=CARTESIAN_POINT('',(-56.1975,-31.75,-7.11200000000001));
#709=DIRECTION('',(-1.,0.,0.));
#710=DIRECTION('',(0.,0.,1.));
#711=AXIS2_PLACEMENT_3D('',#708,#709,#710);
#712=CYLINDRICAL_SURFACE('',#711,4.2545);
#713=ORIENTED_EDGE('',*,*,#383,.F.);
#714=EDGE_LOOP('',(#713));
#715=FACE_BOUND('',#714,.T.);
#716=CARTESIAN_POINT('',(-58.7375,-31.75,-7.112));
#717=DIRECTION('',(-1.,0.,0.));
#718=DIRECTION('',(0.,0.,1.));
#719=AXIS2_PLACEMENT_3D('',#716,#717,#718);
#720=CIRCLE('',#719,4.2545);
#721=CARTESIAN_POINT('',(-58.7375,-31.75,-2.8575));
#722=VERTEX_POINT('',#721);
#723=EDGE_CURVE('E112',#722,#722,#720,.T.);
#724=ORIENTED_EDGE('',*,*,#723,.T.);
#725=EDGE_LOOP('',(#724));
#726=FACE_BOUND('',#725,.T.);
#727=ADVANCED_FACE('F40',(#715,#726),#712,.F.);
#728=CARTESIAN_POINT('',(0.,0.,-16.002));
#729=DIRECTION('',(0.,0.,1.));
#730=DIRECTION('',(1.,0.,0.));
#731=AXIS2_PLACEMENT_3D('',#728,#729,#730);
#732=PLANE('',#731);
#733=ORIENTED_EDGE('',*,*,#503,.F.);
#734=EDGE_LOOP('',(#733));
#735=FACE_BOUND('',#734,.T.);
#736=ORIENTED_EDGE('',*,*,#483,.F.);
#737=EDGE_LOOP('',(#736));
#738=FACE_BOUND('',#737,.T.);
#739=ORIENTED_EDGE('',*,*,#463,.F.);
#740=EDGE_LOOP('',(#739));
#741=FACE_BOUND('',#740,.T.);
#742=ORIENTED_EDGE('',*,*,#443,.F.);
#743=EDGE_LOOP('',(#742));
#744=FACE_BOUND('',#743,.T.);
#745=ORIENTED_EDGE('',*,*,#423,.F.);
#746=EDGE_LOOP('',(#745));
#747=FACE_BOUND('',#746,.T.);
#748=ORIENTED_EDGE('',*,*,#403,.F.);
#749=EDGE_LOOP('',(#748));
#750=FACE_BOUND('',#749,.T.);
#751=DIRECTION('',(1.,0.,0.));
#752=VECTOR('',#751,1.);
#753=CARTESIAN_POINT('',(0.,-38.1,-16.002));
#754=LINE('',#753,#752);
#755=CARTESIAN_POINT('',(58.7375,-38.1,-16.002));
#756=VERTEX_POINT('',#755);
#757=CARTESIAN_POINT('',(-58.7375,-38.1,-16.002));
#758=VERTEX_POINT('',#757);
#759=EDGE_CURVE('E253',#756,#758,#754,.F.);
#760=ORIENTED_EDGE('',*,*,#759,.T.);
#761=DIRECTION('',(0.,1.,0.));
#762=VECTOR('',#761,1.);
#763=CARTESIAN_POINT('',(-58.7375,0.,-16.002));
#764=LINE('',#763,#762);
#765=CARTESIAN_POINT('',(-58.7375,38.1,-16.002));
#766=VERTEX_POINT('',#765);
#767=EDGE_CURVE('E97',#758,#766,#764,.T.);
#768=ORIENTED_EDGE('',*,*,#767,.T.);
#769=DIRECTION('',(1.,0.,0.));
#770=VECTOR('',#769,1.);
#771=CARTESIAN_POINT('',(0.,38.1,-16.002));
#772=LINE('',#771,#770);
#773=CARTESIAN_POINT('',(58.7375,38.1,-16.002));
#774=VERTEX_POINT('',#773);
#775=EDGE_CURVE('E98',#766,#774,#772,.T.);
#776=ORIENTED_EDGE('',*,*,#775,.T.);
#777=DIRECTION('',(0.,1.,0.));
#778=VECTOR('',#777,1.);
#779=CARTESIAN_POINT('',(58.7375,0.,-16.002));
#780=LINE('',#779,#778);
#781=EDGE_CURVE('E93',#774,#756,#780,.F.);
#782=ORIENTED_EDGE('',*,*,#781,.T.);
#783=EDGE_LOOP('',(#760,#768,#776,#782));
#784=FACE_BOUND('',#783,.T.);
#785=ADVANCED_FACE('F262',(#735,#738,#741,#744,#747,#750,#784),#732,.F.);
#786=CARTESIAN_POINT('',(58.7375,0.,0.));
#787=DIRECTION('',(-1.,0.,0.));
#788=DIRECTION('',(0.,0.,1.));
#789=AXIS2_PLACEMENT_3D('',#786,#787,#788);
#790=PLANE('',#789);
#791=ORIENTED_EDGE('',*,*,#543,.F.);
#792=EDGE_LOOP('',(#791));
#793=FACE_BOUND('',#792,.T.);
#794=ORIENTED_EDGE('',*,*,#523,.F.);
#795=EDGE_LOOP('',(#794));
#796=FACE_BOUND('',#795,.T.);
#797=ORIENTED_EDGE('',*,*,#781,.F.);
#798=DIRECTION('',(0.,0.,-1.));
#799=VECTOR('',#798,1.);
#800=CARTESIAN_POINT('',(58.7375,38.1,0.));
#801=LINE('',#800,#799);
#802=CARTESIAN_POINT('',(58.7375,38.1,16.002));
#803=VERTEX_POINT('',#802);
#804=EDGE_CURVE('E89',#774,#803,#801,.F.);
#805=ORIENTED_EDGE('',*,*,#804,.T.);
#806=DIRECTION('',(0.,1.,0.));
#807=VECTOR('',#806,1.);
#808=CARTESIAN_POINT('',(58.7375,0.,16.002));
#809=LINE('',#808,#807);
#810=CARTESIAN_POINT('',(58.7375,-38.1,16.002));
#811=VERTEX_POINT('',#810);
#812=EDGE_CURVE('E75',#811,#803,#809,.T.);
#813=ORIENTED_EDGE('',*,*,#812,.F.);
#814=DIRECTION('',(0.,0.,1.));
#815=VECTOR('',#814,1.);
#816=CARTESIAN_POINT('',(58.7375,-38.1,0.));
#817=LINE('',#816,#815);
#818=EDGE_CURVE('E115',#811,#756,#817,.F.);
#819=ORIENTED_EDGE('',*,*,#818,.T.);
#820=EDGE_LOOP('',(#797,#805,#813,#819));
#821=FACE_BOUND('',#820,.T.);
#822=ADVANCED_FACE('F90',(#793,#796,#821),#790,.F.);
#823=CARTESIAN_POINT('',(0.,38.1,0.));
#824=DIRECTION('',(0.,-1.,0.));
#825=DIRECTION('',(0.,0.,-1.));
#826=AXIS2_PLACEMENT_3D('',#823,#824,#825);
#827=PLANE('',#826);
#828=ORIENTED_EDGE('',*,*,#775,.F.);
#829=DIRECTION('',(0.,0.,-1.));
#830=VECTOR('',#829,1.);
#831=CARTESIAN_POINT('',(-58.7375,38.1,0.));
#832=LINE('',#831,#830);
#833=CARTESIAN_POINT('',(-58.7375,38.1,16.002));
#834=VERTEX_POINT('',#833);
#835=EDGE_CURVE('E102',#766,#834,#832,.F.);
#836=ORIENTED_EDGE('',*,*,#835,.T.);
#837=DIRECTION('',(1.,0.,0.));
#838=VECTOR('',#837,1.);
#839=CARTESIAN_POINT('',(0.,38.1,16.002));
#840=LINE('',#839,#838);
#841=EDGE_CURVE('E79',#803,#834,#840,.F.);
#842=ORIENTED_EDGE('',*,*,#841,.F.);
#843=ORIENTED_EDGE('',*,*,#804,.F.);
#844=EDGE_LOOP('',(#828,#836,#842,#843));
#845=FACE_BOUND('',#844,.T.);
#846=ADVANCED_FACE('F100',(#845),#827,.F.);
#847=CARTESIAN_POINT('',(-58.7375,0.,0.));
#848=DIRECTION('',(1.,0.,0.));
#849=DIRECTION('',(0.,0.,-1.));
#850=AXIS2_PLACEMENT_3D('',#847,#848,#849);
#851=PLANE('',#850);
#852=ORIENTED_EDGE('',*,*,#723,.F.);
#853=EDGE_LOOP('',(#852));
#854=FACE_BOUND('',#853,.T.);
#855=ORIENTED_EDGE('',*,*,#703,.F.);
#856=EDGE_LOOP('',(#855));
#857=FACE_BOUND('',#856,.T.);
#858=ORIENTED_EDGE('',*,*,#683,.F.);
#859=EDGE_LOOP('',(#858));
#860=FACE_BOUND('',#859,.T.);
#861=ORIENTED_EDGE('',*,*,#663,.F.);
#862=EDGE_LOOP('',(#861));
#863=FACE_BOUND('',#862,.T.);
#864=ORIENTED_EDGE('',*,*,#643,.F.);
#865=EDGE_LOOP('',(#864));
#866=FACE_BOUND('',#865,.T.);
#867=ORIENTED_EDGE('',*,*,#623,.F.);
#868=EDGE_LOOP('',(#867));
#869=FACE_BOUND('',#868,.T.);
#870=ORIENTED_EDGE('',*,*,#600,.F.);
#871=EDGE_LOOP('',(#870));
#872=FACE_BOUND('',#871,.T.);
#873=ORIENTED_EDGE('',*,*,#580,.F.);
#874=EDGE_LOOP('',(#873));
#875=FACE_BOUND('',#874,.T.);
#876=ORIENTED_EDGE('',*,*,#563,.F.);
#877=EDGE_LOOP('',(#876));
#878=FACE_BOUND('',#877,.T.);
#879=ORIENTED_EDGE('',*,*,#767,.F.);
#880=DIRECTION('',(0.,0.,1.));
#881=VECTOR('',#880,1.);
#882=CARTESIAN_POINT('',(-58.7375,-38.1,0.));
#883=LINE('',#882,#881);
#884=CARTESIAN_POINT('',(-58.7375,-38.1,16.002));
#885=VERTEX_POINT('',#884);
#886=EDGE_CURVE('E85',#758,#885,#883,.T.);
#887=ORIENTED_EDGE('',*,*,#886,.T.);
#888=DIRECTION('',(0.,1.,0.));
#889=VECTOR('',#888,1.);
#890=CARTESIAN_POINT('',(-58.7375,0.,16.002));
#891=LINE('',#890,#889);
#892=EDGE_CURVE('E62',#834,#885,#891,.F.);
#893=ORIENTED_EDGE('',*,*,#892,.F.);
#894=ORIENTED_EDGE('',*,*,#835,.F.);
#895=EDGE_LOOP('',(#879,#887,#893,#894));
#896=FACE_BOUND('',#895,.T.);
#897=ADVANCED_FACE('F452',(#854,#857,#860,#863,#866,#869,#872,#875,#878,#896),#851,.F.);
#898=CARTESIAN_POINT('',(0.,-38.1,0.));
#899=DIRECTION('',(0.,1.,0.));
#900=DIRECTION('',(0.,0.,1.));
#901=AXIS2_PLACEMENT_3D('',#898,#899,#900);
#902=PLANE('',#901);
#903=ORIENTED_EDGE('',*,*,#759,.F.);
#904=ORIENTED_EDGE('',*,*,#818,.F.);
#905=DIRECTION('',(1.,0.,0.));
#906=VECTOR('',#905,1.);
#907=CARTESIAN_POINT('',(0.,-38.1,16.002));
#908=LINE('',#907,#906);
#909=EDGE_CURVE('E82',#885,#811,#908,.T.);
#910=ORIENTED_EDGE('',*,*,#909,.F.);
#911=ORIENTED_EDGE('',*,*,#886,.F.);
#912=EDGE_LOOP('',(#903,#904,#910,#911));
#913=FACE_BOUND('',#912,.T.);
#914=ADVANCED_FACE('F259',(#913),#902,.F.);
#915=CARTESIAN_POINT('',(0.744681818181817,0.,9.39800000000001));
#916=DIRECTION('',(0.,0.,1.));
#917=DIRECTION('',(1.,0.,0.));
#918=AXIS2_PLACEMENT_3D('',#915,#916,#917);
#919=PLANE('',#918);
#920=DIRECTION('',(0.,-1.,0.));
#921=VECTOR('',#920,1.);
#922=CARTESIAN_POINT('',(0.,0.,9.39800000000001));
#923=LINE('',#922,#921);
#924=CARTESIAN_POINT('',(0.,8.19149999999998,9.39800000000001));
#925=VERTEX_POINT('',#924);
#926=CARTESIAN_POINT('',(0.,0.,9.39800000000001));
#927=VERTEX_POINT('',#926);
#928=EDGE_CURVE('E334',#925,#927,#923,.T.);
#929=ORIENTED_EDGE('',*,*,#928,.F.);
#930=CARTESIAN_POINT('',(0.,0.,9.39800000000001));
#931=DIRECTION('',(0.,0.,1.));
#932=DIRECTION('',(1.,0.,0.));
#933=AXIS2_PLACEMENT_3D('',#930,#931,#932);
#934=CIRCLE('',#933,8.19149999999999);
#935=CARTESIAN_POINT('',(-2.794,-7.7002750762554,9.39800000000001));
#936=VERTEX_POINT('',#935);
#937=EDGE_CURVE('E109',#925,#936,#934,.T.);
#938=ORIENTED_EDGE('',*,*,#937,.T.);
#939=DIRECTION('',(0.,-1.,0.));
#940=VECTOR('',#939,1.);
#941=CARTESIAN_POINT('',(-2.794,0.,9.39800000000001));
#942=LINE('',#941,#940);
#943=CARTESIAN_POINT('',(-2.794,0.,9.39800000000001));
#944=VERTEX_POINT('',#943);
#945=EDGE_CURVE('E231',#944,#936,#942,.T.);
#946=ORIENTED_EDGE('',*,*,#945,.F.);
#947=DIRECTION('',(-1.,0.,0.));
#948=VECTOR('',#947,1.);
#949=CARTESIAN_POINT('',(0.744681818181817,0.,9.39800000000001));
#950=LINE('',#949,#948);
#951=EDGE_CURVE('E235',#927,#944,#950,.T.);
#952=ORIENTED_EDGE('',*,*,#951,.F.);
#953=EDGE_LOOP('',(#929,#938,#946,#952));
#954=FACE_BOUND('',#953,.T.);
#955=ADVANCED_FACE('F357',(#954),#919,.T.);
#956=CARTESIAN_POINT('',(0.,0.,16.002));
#957=DIRECTION('',(0.,0.,1.));
#958=DIRECTION('',(1.,0.,0.));
#959=AXIS2_PLACEMENT_3D('',#956,#957,#958);
#960=PLANE('',#959);
#961=CARTESIAN_POINT('',(46.1899,33.6804,16.002));
#962=DIRECTION('',(0.,0.,1.));
#963=DIRECTION('',(1.,0.,0.));
#964=AXIS2_PLACEMENT_3D('',#961,#962,#963);
#965=CIRCLE('',#964,1.72719999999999);
#966=CARTESIAN_POINT('',(47.9171,33.6804,16.002));
#967=VERTEX_POINT('',#966);
#968=EDGE_CURVE('E312',#967,#967,#965,.T.);
#969=ORIENTED_EDGE('',*,*,#968,.F.);
#970=EDGE_LOOP('',(#969));
#971=FACE_BOUND('',#970,.T.);
#972=CARTESIAN_POINT('',(46.1899,-33.6804,16.002));
#973=DIRECTION('',(0.,0.,1.));
#974=DIRECTION('',(1.,0.,0.));
#975=AXIS2_PLACEMENT_3D('',#972,#973,#974);
#976=CIRCLE('',#975,1.72719999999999);
#977=CARTESIAN_POINT('',(47.9171,-33.6804,16.002));
#978=VERTEX_POINT('',#977);
#979=EDGE_CURVE('E311',#978,#978,#976,.T.);
#980=ORIENTED_EDGE('',*,*,#979,.F.);
#981=EDGE_LOOP('',(#980));
#982=FACE_BOUND('',#981,.T.);
#983=DIRECTION('',(0.,-1.,0.));
#984=VECTOR('',#983,1.);
#985=CARTESIAN_POINT('',(0.,0.,16.002));
#986=LINE('',#985,#984);
#987=CARTESIAN_POINT('',(0.,33.0004046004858,16.002));
#988=VERTEX_POINT('',#987);
#989=CARTESIAN_POINT('',(0.,8.19149999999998,16.002));
#990=VERTEX_POINT('',#989);
#991=EDGE_CURVE('E322',#988,#990,#986,.T.);
#992=ORIENTED_EDGE('',*,*,#991,.F.);
#993=CARTESIAN_POINT('',(0.,0.,16.002));
#994=DIRECTION('',(0.,0.,1.));
#995=DIRECTION('',(1.,0.,0.));
#996=AXIS2_PLACEMENT_3D('',#993,#994,#995);
#997=CIRCLE('',#996,33.0004046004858);
#998=CARTESIAN_POINT('',(-2.794,-32.881913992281,16.002));
#999=VERTEX_POINT('',#998);
#1000=EDGE_CURVE('E336',#999,#988,#997,.T.);
#1001=ORIENTED_EDGE('',*,*,#1000,.F.);
#1002=DIRECTION('',(0.,-1.,0.));
#1003=VECTOR('',#1002,1.);
#1004=CARTESIAN_POINT('',(-2.794,0.,16.002));
#1005=LINE('',#1004,#1003);
#1006=CARTESIAN_POINT('',(-2.794,-7.7002750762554,16.002));
#1007=VERTEX_POINT('',#1006);
#1008=EDGE_CURVE('E340',#1007,#999,#1005,.T.);
#1009=ORIENTED_EDGE('',*,*,#1008,.F.);
#1010=CARTESIAN_POINT('',(0.,0.,16.002));
#1011=DIRECTION('',(0.,0.,1.));
#1012=DIRECTION('',(1.,0.,0.));
#1013=AXIS2_PLACEMENT_3D('',#1010,#1011,#1012);
#1014=CIRCLE('',#1013,8.19149999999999);
#1015=EDGE_CURVE('E46',#1007,#990,#1014,.F.);
#1016=ORIENTED_EDGE('',*,*,#1015,.T.);
#1017=EDGE_LOOP('',(#992,#1001,#1009,#1016));
#1018=FACE_BOUND('',#1017,.T.);
#1019=ORIENTED_EDGE('',*,*,#892,.T.);
#1020=ORIENTED_EDGE('',*,*,#909,.T.);
#1021=ORIENTED_EDGE('',*,*,#812,.T.);
#1022=ORIENTED_EDGE('',*,*,#841,.T.);
#1023=EDGE_LOOP('',(#1019,#1020,#1021,#1022));
#1024=FACE_BOUND('',#1023,.T.);
#1025=ADVANCED_FACE('F77',(#971,#982,#1018,#1024),#960,.T.);
#1026=CARTESIAN_POINT('',(0.,0.,9.39800000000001));
#1027=DIRECTION('',(0.,0.,1.));
#1028=DIRECTION('',(1.,0.,0.));
#1029=AXIS2_PLACEMENT_3D('',#1026,#1027,#1028);
#1030=CYLINDRICAL_SURFACE('',#1029,8.19149999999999);
#1031=ORIENTED_EDGE('',*,*,#937,.F.);
#1032=DIRECTION('',(0.,0.,1.));
#1033=VECTOR('',#1032,1.);
#1034=CARTESIAN_POINT('',(0.,8.19149999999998,9.39800000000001));
#1035=LINE('',#1034,#1033);
#1036=EDGE_CURVE('E329',#925,#990,#1035,.T.);
#1037=ORIENTED_EDGE('',*,*,#1036,.T.);
#1038=ORIENTED_EDGE('',*,*,#1015,.F.);
#1039=DIRECTION('',(0.,0.,1.));
#1040=VECTOR('',#1039,1.);
#1041=CARTESIAN_POINT('',(-2.794,-7.7002750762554,9.39800000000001));
#1042=LINE('',#1041,#1040);
#1043=EDGE_CURVE('E11',#1007,#936,#1042,.F.);
#1044=ORIENTED_EDGE('',*,*,#1043,.T.);
#1045=EDGE_LOOP('',(#1031,#1037,#1038,#1044));
#1046=FACE_BOUND('',#1045,.T.);
#1047=ADVANCED_FACE('F360',(#1046),#1030,.F.);
#1048=CARTESIAN_POINT('',(0.,0.,5.842));
#1049=DIRECTION('',(0.,0.,1.));
#1050=DIRECTION('',(1.,0.,0.));
#1051=AXIS2_PLACEMENT_3D('',#1048,#1049,#1050);
#1052=CYLINDRICAL_SURFACE('',#1051,33.0004046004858);
#1053=ORIENTED_EDGE('',*,*,#1000,.T.);
#1054=DIRECTION('',(0.,0.,1.));
#1055=VECTOR('',#1054,1.);
#1056=CARTESIAN_POINT('',(0.,33.0004046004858,5.842));
#1057=LINE('',#1056,#1055);
#1058=CARTESIAN_POINT('',(0.,33.0004046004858,5.842));
#1059=VERTEX_POINT('',#1058);
#1060=EDGE_CURVE('E324',#1059,#988,#1057,.T.);
#1061=ORIENTED_EDGE('',*,*,#1060,.F.);
#1062=CARTESIAN_POINT('',(0.,0.,5.842));
#1063=DIRECTION('',(0.,0.,1.));
#1064=DIRECTION('',(1.,0.,0.));
#1065=AXIS2_PLACEMENT_3D('',#1062,#1063,#1064);
#1066=CIRCLE('',#1065,33.0004046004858);
#1067=CARTESIAN_POINT('',(-2.794,-32.881913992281,5.842));
#1068=VERTEX_POINT('',#1067);
#1069=EDGE_CURVE('E337',#1068,#1059,#1066,.T.);
#1070=ORIENTED_EDGE('',*,*,#1069,.F.);
#1071=DIRECTION('',(0.,0.,1.));
#1072=VECTOR('',#1071,1.);
#1073=CARTESIAN_POINT('',(-2.794,-32.881913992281,5.842));
#1074=LINE('',#1073,#1072);
#1075=EDGE_CURVE('E243',#1068,#999,#1074,.T.);
#1076=ORIENTED_EDGE('',*,*,#1075,.T.);
#1077=EDGE_LOOP('',(#1053,#1061,#1070,#1076));
#1078=FACE_BOUND('',#1077,.T.);
#1079=ADVANCED_FACE('F368',(#1078),#1052,.F.);
#1080=CARTESIAN_POINT('',(-2.794,0.,5.842));
#1081=DIRECTION('',(-1.,0.,0.));
#1082=DIRECTION('',(0.,-1.,0.));
#1083=AXIS2_PLACEMENT_3D('',#1080,#1081,#1082);
#1084=PLANE('',#1083);
#1085=ORIENTED_EDGE('',*,*,#945,.T.);
#1086=ORIENTED_EDGE('',*,*,#1043,.F.);
#1087=ORIENTED_EDGE('',*,*,#1008,.T.);
#1088=ORIENTED_EDGE('',*,*,#1075,.F.);
#1089=DIRECTION('',(0.,-1.,0.));
#1090=VECTOR('',#1089,1.);
#1091=CARTESIAN_POINT('',(-2.794,0.,5.842));
#1092=LINE('',#1091,#1090);
#1093=CARTESIAN_POINT('',(-2.794,0.,5.842));
#1094=VERTEX_POINT('',#1093);
#1095=EDGE_CURVE('E342',#1094,#1068,#1092,.T.);
#1096=ORIENTED_EDGE('',*,*,#1095,.F.);
#1097=DIRECTION('',(0.,0.,1.));
#1098=VECTOR('',#1097,1.);
#1099=CARTESIAN_POINT('',(-2.794,0.,5.842));
#1100=LINE('',#1099,#1098);
#1101=EDGE_CURVE('E345',#1094,#944,#1100,.T.);
#1102=ORIENTED_EDGE('',*,*,#1101,.T.);
#1103=EDGE_LOOP('',(#1085,#1086,#1087,#1088,#1096,#1102));
#1104=FACE_BOUND('',#1103,.T.);
#1105=ADVANCED_FACE('F351',(#1104),#1084,.F.);
#1106=CARTESIAN_POINT('',(-2.794,0.,5.842));
#1107=DIRECTION('',(0.,1.,0.));
#1108=DIRECTION('',(-1.,0.,0.));
#1109=AXIS2_PLACEMENT_3D('',#1106,#1107,#1108);
#1110=PLANE('',#1109);
#1111=DIRECTION('',(-1.,0.,0.));
#1112=VECTOR('',#1111,1.);
#1113=CARTESIAN_POINT('',(-2.794,0.,5.842));
#1114=LINE('',#1113,#1112);
#1115=CARTESIAN_POINT('',(0.,0.,5.842));
#1116=VERTEX_POINT('',#1115);
#1117=EDGE_CURVE('E339',#1116,#1094,#1114,.T.);
#1118=ORIENTED_EDGE('',*,*,#1117,.F.);
#1119=DIRECTION('',(0.,0.,1.));
#1120=VECTOR('',#1119,1.);
#1121=CARTESIAN_POINT('',(0.,0.,5.842));
#1122=LINE('',#1121,#1120);
#1123=EDGE_CURVE('E326',#1116,#927,#1122,.T.);
#1124=ORIENTED_EDGE('',*,*,#1123,.T.);
#1125=ORIENTED_EDGE('',*,*,#951,.T.);
#1126=ORIENTED_EDGE('',*,*,#1101,.F.);
#1127=EDGE_LOOP('',(#1118,#1124,#1125,#1126));
#1128=FACE_BOUND('',#1127,.T.);
#1129=ADVANCED_FACE('F372',(#1128),#1110,.F.);
#1130=CARTESIAN_POINT('',(0.,0.,5.842));
#1131=DIRECTION('',(0.,0.,1.));
#1132=DIRECTION('',(1.,0.,0.));
#1133=AXIS2_PLACEMENT_3D('',#1130,#1131,#1132);
#1134=PLANE('',#1133);
#1135=ORIENTED_EDGE('',*,*,#1069,.T.);
#1136=DIRECTION('',(0.,-1.,0.));
#1137=VECTOR('',#1136,1.);
#1138=CARTESIAN_POINT('',(0.,0.,5.842));
#1139=LINE('',#1138,#1137);
#1140=EDGE_CURVE('E53',#1059,#1116,#1139,.T.);
#1141=ORIENTED_EDGE('',*,*,#1140,.T.);
#1142=ORIENTED_EDGE('',*,*,#1117,.T.);
#1143=ORIENTED_EDGE('',*,*,#1095,.T.);
#1144=EDGE_LOOP('',(#1135,#1141,#1142,#1143));
#1145=FACE_BOUND('',#1144,.T.);
#1146=ADVANCED_FACE('F373',(#1145),#1134,.T.);
#1147=CARTESIAN_POINT('',(0.,0.,5.842));
#1148=DIRECTION('',(-1.,0.,0.));
#1149=DIRECTION('',(0.,0.,1.));
#1150=AXIS2_PLACEMENT_3D('',#1147,#1148,#1149);
#1151=PLANE('',#1150);
#1152=ORIENTED_EDGE('',*,*,#928,.T.);
#1153=ORIENTED_EDGE('',*,*,#1123,.F.);
#1154=ORIENTED_EDGE('',*,*,#1140,.F.);
#1155=ORIENTED_EDGE('',*,*,#1060,.T.);
#1156=ORIENTED_EDGE('',*,*,#991,.T.);
#1157=ORIENTED_EDGE('',*,*,#1036,.F.);
#1158=EDGE_LOOP('',(#1152,#1153,#1154,#1155,#1156,#1157));
#1159=FACE_BOUND('',#1158,.T.);
#1160=ADVANCED_FACE('F371',(#1159),#1151,.F.);
#1161=CARTESIAN_POINT('',(46.1899,-33.6804,3.70839999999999));
#1162=DIRECTION('',(0.,0.,1.));
#1163=DIRECTION('',(1.,0.,0.));
#1164=AXIS2_PLACEMENT_3D('',#1161,#1162,#1163);
#1165=CONICAL_SURFACE('',#1164,1.72719999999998,1.02974425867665);
#1166=CARTESIAN_POINT('',(46.1899,-33.6804,2.6705935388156));
#1167=VERTEX_POINT('',#1166);
#1168=VERTEX_LOOP('',#1167);
#1169=FACE_BOUND('',#1168,.T.);
#1170=CARTESIAN_POINT('',(46.1899,-33.6804,3.70839999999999));
#1171=DIRECTION('',(0.,0.,1.));
#1172=DIRECTION('',(1.,0.,0.));
#1173=AXIS2_PLACEMENT_3D('',#1170,#1171,#1172);
#1174=CIRCLE('',#1173,1.72719999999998);
#1175=CARTESIAN_POINT('',(47.9171,-33.6804,3.70839999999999));
#1176=VERTEX_POINT('',#1175);
#1177=EDGE_CURVE('E315',#1176,#1176,#1174,.T.);
#1178=ORIENTED_EDGE('',*,*,#1177,.T.);
#1179=EDGE_LOOP('',(#1178));
#1180=FACE_BOUND('',#1179,.T.);
#1181=ADVANCED_FACE('F380',(#1169,#1180),#1165,.F.);
#1182=CARTESIAN_POINT('',(46.1899,-33.6804,16.002));
#1183=DIRECTION('',(0.,0.,1.));
#1184=DIRECTION('',(1.,0.,0.));
#1185=AXIS2_PLACEMENT_3D('',#1182,#1183,#1184);
#1186=CYLINDRICAL_SURFACE('',#1185,1.72719999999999);
#1187=ORIENTED_EDGE('',*,*,#1177,.F.);
#1188=EDGE_LOOP('',(#1187));
#1189=FACE_BOUND('',#1188,.T.);
#1190=ORIENTED_EDGE('',*,*,#979,.T.);
#1191=EDGE_LOOP('',(#1190));
#1192=FACE_BOUND('',#1191,.T.);
#1193=ADVANCED_FACE('F305',(#1189,#1192),#1186,.F.);
#1194=CARTESIAN_POINT('',(46.1899,33.6804,3.70839999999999));
#1195=DIRECTION('',(0.,0.,1.));
#1196=DIRECTION('',(1.,0.,0.));
#1197=AXIS2_PLACEMENT_3D('',#1194,#1195,#1196);
#1198=CONICAL_SURFACE('',#1197,1.72719999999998,1.02974425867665);
#1199=CARTESIAN_POINT('',(46.1899,33.6804,2.6705935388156));
#1200=VERTEX_POINT('',#1199);
#1201=VERTEX_LOOP('',#1200);
#1202=FACE_BOUND('',#1201,.T.);
#1203=CARTESIAN_POINT('',(46.1899,33.6804,3.70839999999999));
#1204=DIRECTION('',(0.,0.,1.));
#1205=DIRECTION('',(1.,0.,0.));
#1206=AXIS2_PLACEMENT_3D('',#1203,#1204,#1205);
#1207=CIRCLE('',#1206,1.72719999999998);
#1208=CARTESIAN_POINT('',(47.9171,33.6804,3.70839999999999));
#1209=VERTEX_POINT('',#1208);
#1210=EDGE_CURVE('E309',#1209,#1209,#1207,.T.);
#1211=ORIENTED_EDGE('',*,*,#1210,.T.);
#1212=EDGE_LOOP('',(#1211));
#1213=FACE_BOUND('',#1212,.T.);
#1214=ADVANCED_FACE('F301',(#1202,#1213),#1198,.F.);
#1215=CARTESIAN_POINT('',(46.1899,33.6804,16.002));
#1216=DIRECTION('',(0.,0.,1.));
#1217=DIRECTION('',(1.,0.,0.));
#1218=AXIS2_PLACEMENT_3D('',#1215,#1216,#1217);
#1219=CYLINDRICAL_SURFACE('',#1218,1.72719999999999);
#1220=ORIENTED_EDGE('',*,*,#1210,.F.);
#1221=EDGE_LOOP('',(#1220));
#1222=FACE_BOUND('',#1221,.T.);
#1223=ORIENTED_EDGE('',*,*,#968,.T.);
#1224=EDGE_LOOP('',(#1223));
#1225=FACE_BOUND('',#1224,.T.);
#1226=ADVANCED_FACE('F304',(#1222,#1225),#1219,.F.);
#1227=CLOSED_SHELL('',(#35,#52,#72,#92,#109,#126,#143,#160,#177,#194,#214,#234,#251,#268,#285,
#302,#319,#336,#353,#370,#387,#407,#427,#447,#467,#487,#507,#527,#547,#567,#587,#607,#627,#647,
#667,#687,#707,#727,#785,#822,#846,#897,#914,#955,#1025,#1047,#1079,#1105,#1129,#1146,#1160,
#1181,#1193,#1214,#1226));
#1228=CARTESIAN_POINT('',(-55.785,19.5036276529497,0.));
#1229=DIRECTION('',(1.,0.,0.));
#1230=DIRECTION('',(0.,0.,-1.));
#1231=AXIS2_PLACEMENT_3D('',#1228,#1229,#1230);
#1232=PLANE('',#1231);
#1233=CARTESIAN_POINT('',(-55.785,19.05,0.));
#1234=DIRECTION('',(1.,0.,0.));
#1235=DIRECTION('',(0.,0.,-1.));
#1236=AXIS2_PLACEMENT_3D('',#1233,#1234,#1235);
#1237=CIRCLE('',#1236,4.9899041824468);
#1238=CARTESIAN_POINT('',(-55.785,19.05,-4.9899041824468));
#1239=VERTEX_POINT('',#1238);
#1240=EDGE_CURVE('E229',#1239,#1239,#1237,.T.);
#1241=ORIENTED_EDGE('',*,*,#1240,.F.);
#1242=EDGE_LOOP('',(#1241));
#1243=FACE_BOUND('',#1242,.T.);
#1244=ADVANCED_FACE('F584',(#1243),#1232,.F.);
#1245=CARTESIAN_POINT('',(-57.785,19.05,0.));
#1246=DIRECTION('',(1.,0.,0.));
#1247=DIRECTION('',(0.,0.,-1.));
#1248=AXIS2_PLACEMENT_3D('',#1245,#1246,#1247);
#1249=CYLINDRICAL_SURFACE('',#1248,4.9899041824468);
#1250=ORIENTED_EDGE('',*,*,#1240,.T.);
#1251=EDGE_LOOP('',(#1250));
#1252=FACE_BOUND('',#1251,.T.);
#1253=CARTESIAN_POINT('',(-57.785,19.05,0.));
#1254=DIRECTION('',(1.,0.,0.));
#1255=DIRECTION('',(0.,0.,-1.));
#1256=AXIS2_PLACEMENT_3D('',#1253,#1254,#1255);
#1257=CIRCLE('',#1256,4.9899041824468);
#1258=CARTESIAN_POINT('',(-57.785,19.05,-4.9899041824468));
#1259=VERTEX_POINT('',#1258);
#1260=EDGE_CURVE('E227',#1259,#1259,#1257,.F.);
#1261=ORIENTED_EDGE('',*,*,#1260,.T.);
#1262=EDGE_LOOP('',(#1261));
#1263=FACE_BOUND('',#1262,.T.);
#1264=ADVANCED_FACE('F573',(#1252,#1263),#1249,.F.);
#1265=CARTESIAN_POINT('',(-57.785,19.5036276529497,0.));
#1266=DIRECTION('',(1.,0.,0.));
#1267=DIRECTION('',(0.,0.,-1.));
#1268=AXIS2_PLACEMENT_3D('',#1265,#1266,#1267);
#1269=PLANE('',#1268);
#1270=ORIENTED_EDGE('',*,*,#1260,.F.);
#1271=EDGE_LOOP('',(#1270));
#1272=FACE_BOUND('',#1271,.T.);
#1273=ADVANCED_FACE('F569',(#1272),#1269,.T.);
#1274=CLOSED_SHELL('',(#1244,#1264,#1273));
#1275=ORIENTED_CLOSED_SHELL('',*,#1274,.T.);
#1276=BREP_WITH_VOIDS('B2',#1227,(#1275));
#1277=ADVANCED_BREP_SHAPE_REPRESENTATION('',(#18,#1276),#14);
#1278=SHAPE_DEFINITION_REPRESENTATION(#9,#1277);
ENDSEC;
END-ISO-10303-21;
